One B-rep face of a CAD part: STEP entity #656.
In plain terms, the cylindrical face has radius 42.5 mm (diameter 85 mm), a partial arc.
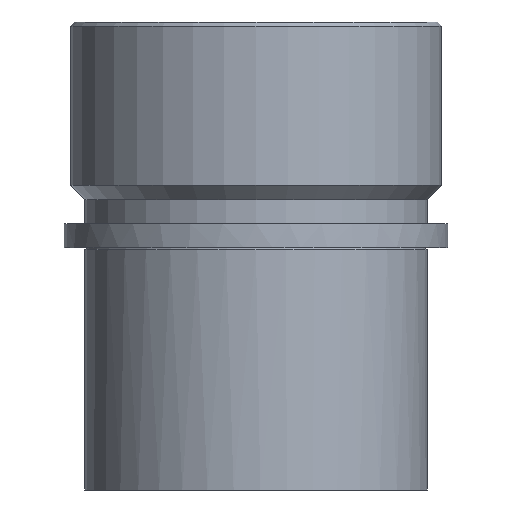
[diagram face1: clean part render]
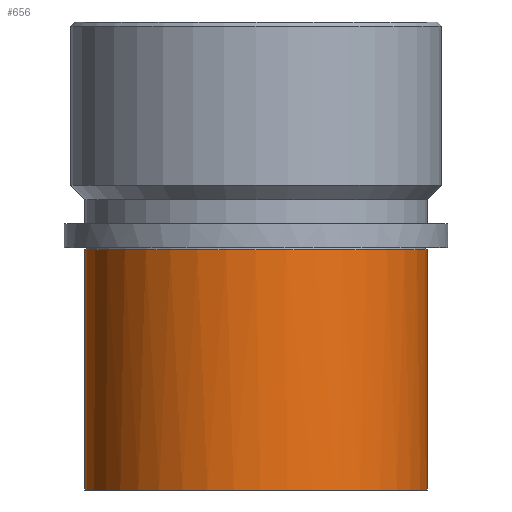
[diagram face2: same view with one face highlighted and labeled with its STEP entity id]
Its self-contained STEP definition (entity closure, numbers rounded to 3 decimals):
#428=CARTESIAN_POINT('Control Point',(-42.5,0.,-60.)) ;
#429=CARTESIAN_POINT('Control Point',(-42.5,-4.152,-60.)) ;
#430=CARTESIAN_POINT('Control Point',(-41.993,-8.304,-60.)) ;
#431=CARTESIAN_POINT('Control Point',(-40.979,-12.373,-60.)) ;
#432=CARTESIAN_POINT('Control Point',(-37.978,-20.182,-60.)) ;
#433=CARTESIAN_POINT('Control Point',(-33.186,-27.038,-60.)) ;
#434=CARTESIAN_POINT('Control Point',(-30.381,-30.156,-60.)) ;
#435=CARTESIAN_POINT('Control Point',(-24.066,-35.643,-60.)) ;
#436=CARTESIAN_POINT('Control Point',(-16.617,-39.449,-60.)) ;
#437=CARTESIAN_POINT('Control Point',(-12.677,-40.886,-60.)) ;
#438=CARTESIAN_POINT('Control Point',(-4.526,-42.768,-60.)) ;
#439=CARTESIAN_POINT('Control Point',(3.838,-42.634,-60.)) ;
#440=CARTESIAN_POINT('Control Point',(7.992,-42.053,-60.)) ;
#441=CARTESIAN_POINT('Control Point',(16.073,-39.891,-60.)) ;
#442=CARTESIAN_POINT('Control Point',(23.396,-35.847,-60.)) ;
#443=CARTESIAN_POINT('Control Point',(26.791,-33.385,-60.)) ;
#444=CARTESIAN_POINT('Control Point',(32.912,-27.683,-60.)) ;
#445=CARTESIAN_POINT('Control Point',(37.481,-20.676,-60.)) ;
#446=CARTESIAN_POINT('Control Point',(39.325,-16.909,-60.)) ;
#447=CARTESIAN_POINT('Control Point',(41.279,-11.248,-60.)) ;
#448=CARTESIAN_POINT('Control Point',(42.217,-5.37,-60.)) ;
#449=CARTESIAN_POINT('Control Point',(42.406,-3.585,-60.)) ;
#450=CARTESIAN_POINT('Control Point',(42.5,-1.792,-60.)) ;
#451=CARTESIAN_POINT('Control Point',(42.5,0.,-60.)) ;
#452=CARTESIAN_POINT('Vertex',(-42.5,0.,-60.)) ;
#454=CARTESIAN_POINT('Vertex',(42.5,0.,-60.)) ;
#626=CARTESIAN_POINT('Axis2P3D Location',(0.,0.,56.)) ;
#631=CARTESIAN_POINT('Line Origine',(42.5,0.,56.)) ;
#635=CARTESIAN_POINT('Vertex',(42.5,0.,-0.5)) ;
#638=CARTESIAN_POINT('Axis2P3D Location',(0.,0.,-0.5)) ;
#642=CARTESIAN_POINT('Vertex',(-42.5,0.,-0.5)) ;
#645=CARTESIAN_POINT('Line Origine',(-42.5,0.,56.)) ;
#627=DIRECTION('Axis2P3D Direction',(0.,0.,-1.)) ;
#628=DIRECTION('Axis2P3D XDirection',(1.,0.,0.)) ;
#632=DIRECTION('Vector Direction',(0.,0.,-1.)) ;
#639=DIRECTION('Axis2P3D Direction',(0.,0.,-1.)) ;
#646=DIRECTION('Vector Direction',(0.,0.,-1.)) ;
#629=AXIS2_PLACEMENT_3D('Cylinder Axis2P3D',#626,#627,#628) ;
#640=AXIS2_PLACEMENT_3D('Circle Axis2P3D',#638,#639,$) ;
#651=ORIENTED_EDGE('',*,*,#637,.T.) ;
#652=ORIENTED_EDGE('',*,*,#644,.F.) ;
#653=ORIENTED_EDGE('',*,*,#649,.T.) ;
#654=ORIENTED_EDGE('',*,*,#456,.T.) ;
#633=VECTOR('Line Direction',#632,1.) ;
#647=VECTOR('Line Direction',#646,1.) ;
#656=ADVANCED_FACE('741-63',(#655),#630,.T.) ;
#427=B_SPLINE_CURVE_WITH_KNOTS('',5,(#428,#429,#430,#431,#432,#433,#434,#435,#436,#437,#438,#439,#440,#441,#442,#443,#444,#445,#446,#447,#448,#449,#450,#451),.UNSPECIFIED.,.F.,.U.,(6,3,3,3,3,3,3,6),(0.,29.358,58.716,88.073,117.431,146.789,176.147,188.821),.UNSPECIFIED.) ;
#641=CIRCLE('generated circle',#640,42.5) ;
#630=CYLINDRICAL_SURFACE('generated cylinder',#629,42.5) ;
#456=EDGE_CURVE('',#453,#455,#427,.T.) ;
#637=EDGE_CURVE('',#455,#636,#634,.F.) ;
#644=EDGE_CURVE('',#643,#636,#641,.F.) ;
#649=EDGE_CURVE('',#643,#453,#648,.T.) ;
#650=EDGE_LOOP('',(#651,#652,#653,#654)) ;
#655=FACE_OUTER_BOUND('',#650,.T.) ;
#634=LINE('Line',#631,#633) ;
#648=LINE('Line',#645,#647) ;
#453=VERTEX_POINT('',#452) ;
#455=VERTEX_POINT('',#454) ;
#636=VERTEX_POINT('',#635) ;
#643=VERTEX_POINT('',#642) ;
